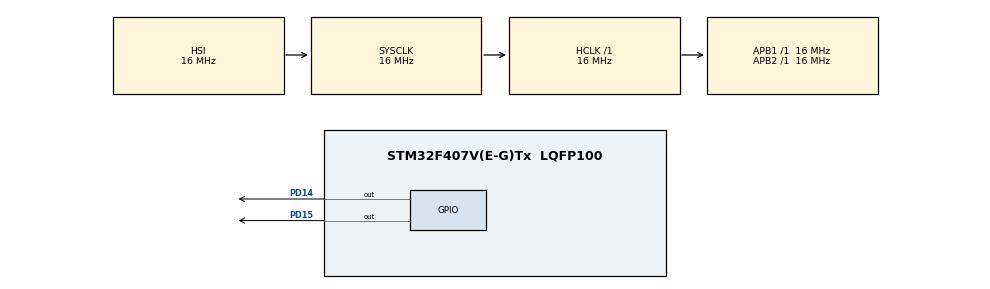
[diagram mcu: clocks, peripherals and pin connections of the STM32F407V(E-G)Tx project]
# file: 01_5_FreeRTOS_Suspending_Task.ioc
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FREERTOS.Tasks01=defaultTask,0,128,StartDefaultTask,Default,NULL,Dynamic,NULL,NULL
FREERTOS.configUSE_TIMERS=1
Mcu.Family=STM32F4
Mcu.Name=STM32F407V(E-G)Tx
Mcu.Package=LQFP100
NVIC.PriorityGroup=NVIC_PRIORITYGROUP_4
PA13.Mode=Trace_Asynchronous_SW
PA13.Signal=SYS_JTMS-SWDIO
PA14.Mode=Trace_Asynchronous_SW
PA14.Signal=SYS_JTCK-SWCLK
PB3.Mode=Trace_Asynchronous_SW
PB3.Signal=SYS_JTDO-SWO
PD14.Signal=GPIO_Output
PD15.Signal=GPIO_Output
ProjectManager.HeapSize=0x200
ProjectManager.StackSize=0x400
ProjectManager.TargetToolchain=STM32CubeIDE
RCC.AHBFreq_Value=16000000
RCC.APB1Freq_Value=16000000
RCC.APB2Freq_Value=16000000
RCC.CortexFreq_Value=16000000
RCC.HSE_VALUE=25000000
RCC.HSI_VALUE=16000000
RCC.LSE_VALUE=32768
RCC.SYSCLKFreq_VALUE=16000000
RCC.VCOOutputFreq_Value=192000000
VP_FREERTOS_VS_CMSIS_V1.Mode=CMSIS_V1
board=custom

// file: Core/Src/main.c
#include "main.h"
#include "FreeRTOS.h"
#include "task.h"

#include <stdio.h>

int _write(int file,char *ptr, int len)
{
	int i=0;
	for(i=0;i<len;i++)
		ITM_SendChar((*ptr++));
	return len;

}

TaskHandle_t xHandle1,xHandle2;

void SystemClock_Config(void);
static void MX_GPIO_Init(void);

#define RED    GPIO_PIN_14
#define BLUE   GPIO_PIN_15

int i=0,j=0;

void  vBlueLedControllerTask(void *pvParameters)
{

	while(1)
	{
				printf("Blue= %d\n",i);
				HAL_GPIO_WritePin(GPIOD,BLUE,1);
				vTaskDelay( 500 );
				HAL_GPIO_WritePin(GPIOD,BLUE,0);
				vTaskDelay( 500 );

				i=i+1;
				if(i>=10)
					vTaskSuspend(xHandle1);

	}
}

void  vRedLedControllerTask(void *pvParameters)
{
	while(1)
	{
		j+=1;
		printf("Red =%d \n",j);

				HAL_GPIO_WritePin(GPIOD,RED,1);
				vTaskDelay( 500);

				HAL_GPIO_WritePin(GPIOD,RED,0);
				vTaskDelay( 500 );

	}
}

int main(void)
{
  HAL_Init();

  SystemClock_Config();

  MX_GPIO_Init();
  xTaskCreate(vBlueLedControllerTask,
  							 "Blue Led Controller",
  								128,
  								NULL,
  								1,
  								&xHandle1
  								);

  	xTaskCreate(vRedLedControllerTask,
  							 "Red Led Controller",
  								128,
  								NULL,
  								2,
								&xHandle2
  								);

     vTaskStartScheduler();

  while (1)
  {

  }

}

void SystemClock_Config(void)
{
  RCC_OscInitTypeDef RCC_OscInitStruct = {0};
  RCC_ClkInitTypeDef RCC_ClkInitStruct = {0};

  /** Configure the main internal regulator output voltage
  */
  __HAL_RCC_PWR_CLK_ENABLE();
  __HAL_PWR_VOLTAGESCALING_CONFIG(PWR_REGULATOR_VOLTAGE_SCALE1);
  /** Initializes the RCC Oscillators according to the specified parameters
  * in the RCC_OscInitTypeDef structure.
  */
  RCC_OscInitStruct.OscillatorType = RCC_OSCILLATORTYPE_HSI;
  RCC_OscInitStruct.HSIState = RCC_HSI_ON;
  RCC_OscInitStruct.HSICalibrationValue = RCC_HSICALIBRATION_DEFAULT;
  RCC_OscInitStruct.PLL.PLLState = RCC_PLL_NONE;
  if (HAL_RCC_OscConfig(&RCC_OscInitStruct) != HAL_OK)
  {
    Error_Handler();
  }
  /** Initializes the CPU, AHB and APB buses clocks
  */
  RCC_ClkInitStruct.ClockType = RCC_CLOCKTYPE_HCLK|RCC_CLOCKTYPE_SYSCLK
                              |RCC_CLOCKTYPE_PCLK1|RCC_CLOCKTYPE_PCLK2;
  RCC_ClkInitStruct.SYSCLKSource = RCC_SYSCLKSOURCE_HSI;
  RCC_ClkInitStruct.AHBCLKDivider = RCC_SYSCLK_DIV1;
  RCC_ClkInitStruct.APB1CLKDivider = RCC_HCLK_DIV1;
  RCC_ClkInitStruct.APB2CLKDivider = RCC_HCLK_DIV1;

  if (HAL_RCC_ClockConfig(&RCC_ClkInitStruct, FLASH_LATENCY_0) != HAL_OK)
  {
    Error_Handler();
  }
}

static void MX_GPIO_Init(void)
{
  GPIO_InitTypeDef GPIO_InitStruct = {0};

  /* GPIO Ports Clock Enable */
  __HAL_RCC_GPIOC_CLK_ENABLE();
  __HAL_RCC_GPIOD_CLK_ENABLE();
  __HAL_RCC_GPIOA_CLK_ENABLE();
  __HAL_RCC_GPIOB_CLK_ENABLE();

  /*Configure GPIO pin Output Level */
  HAL_GPIO_WritePin(GPIOC, GPIO_PIN_1, GPIO_PIN_RESET);

  /*Configure GPIO pin Output Level */
  HAL_GPIO_WritePin(GPIOD, GPIO_PIN_12|GPIO_PIN_13|GPIO_PIN_14|GPIO_PIN_15, GPIO_PIN_RESET);

  /*Configure GPIO pin : PC1 */
  GPIO_InitStruct.Pin = GPIO_PIN_1;
  GPIO_InitStruct.Mode = GPIO_MODE_OUTPUT_PP;
  GPIO_InitStruct.Pull = GPIO_NOPULL;
  GPIO_InitStruct.Speed = GPIO_SPEED_FREQ_LOW;
  HAL_GPIO_Init(GPIOC, &GPIO_InitStruct);

  /*Configure GPIO pins : PD12 PD13 PD14 PD15 */
  GPIO_InitStruct.Pin = GPIO_PIN_12|GPIO_PIN_13|GPIO_PIN_14|GPIO_PIN_15;
  GPIO_InitStruct.Mode = GPIO_MODE_OUTPUT_PP;
  GPIO_InitStruct.Pull = GPIO_NOPULL;
  GPIO_InitStruct.Speed = GPIO_SPEED_FREQ_LOW;
  HAL_GPIO_Init(GPIOD, &GPIO_InitStruct);

}

void Error_Handler(void)
{
  __disable_irq();
  while (1)
  {
  }
}

/************************ (C) COPYRIGHT STMicroelectronics *****END OF FILE****/
